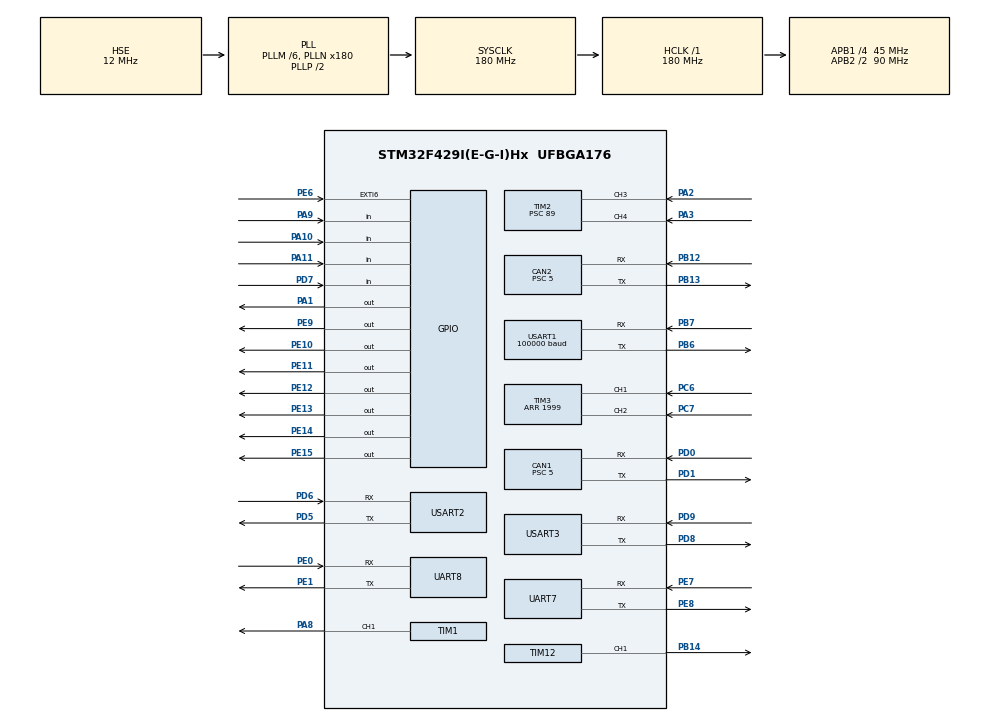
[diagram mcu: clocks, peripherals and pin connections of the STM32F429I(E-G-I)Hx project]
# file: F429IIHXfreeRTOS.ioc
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CAN1.BS1=CAN_BS1_7TQ
CAN1.CalculateTimeQuantum=111.11111111111111
CAN1.Prescaler=5
CAN1.SJW=CAN_SJW_2TQ
CAN2.BS1=CAN_BS1_7TQ
CAN2.CalculateTimeQuantum=111.11111111111111
CAN2.Prescaler=5
CAN2.SJW=CAN_SJW_2TQ
Dma.Request0=UART7_RX
Dma.Request1=USART1_RX
Dma.Request2=USART2_RX
Dma.Request3=USART3_RX
Dma.Request4=UART8_RX
Dma.UART7_RX.0.Direction=DMA_PERIPH_TO_MEMORY
Dma.UART7_RX.0.FIFOMode=DMA_FIFOMODE_DISABLE
Dma.UART7_RX.0.Instance=DMA1_Stream3
Dma.UART7_RX.0.MemDataAlignment=DMA_MDATAALIGN_BYTE
Dma.UART7_RX.0.MemInc=DMA_MINC_ENABLE
Dma.UART7_RX.0.Mode=DMA_NORMAL
Dma.UART7_RX.0.PeriphDataAlignment=DMA_PDATAALIGN_BYTE
Dma.UART7_RX.0.PeriphInc=DMA_PINC_DISABLE
Dma.UART7_RX.0.Priority=DMA_PRIORITY_LOW
Dma.UART8_RX.4.Direction=DMA_PERIPH_TO_MEMORY
Dma.UART8_RX.4.FIFOMode=DMA_FIFOMODE_DISABLE
Dma.UART8_RX.4.Instance=DMA1_Stream6
Dma.UART8_RX.4.MemDataAlignment=DMA_MDATAALIGN_BYTE
Dma.UART8_RX.4.MemInc=DMA_MINC_ENABLE
Dma.UART8_RX.4.Mode=DMA_NORMAL
Dma.UART8_RX.4.PeriphDataAlignment=DMA_PDATAALIGN_BYTE
Dma.UART8_RX.4.PeriphInc=DMA_PINC_DISABLE
Dma.UART8_RX.4.Priority=DMA_PRIORITY_LOW
Dma.USART1_RX.1.Direction=DMA_PERIPH_TO_MEMORY
Dma.USART1_RX.1.FIFOMode=DMA_FIFOMODE_DISABLE
Dma.USART1_RX.1.Instance=DMA2_Stream2
Dma.USART1_RX.1.MemDataAlignment=DMA_MDATAALIGN_BYTE
Dma.USART1_RX.1.MemInc=DMA_MINC_ENABLE
Dma.USART1_RX.1.Mode=DMA_NORMAL
Dma.USART1_RX.1.PeriphDataAlignment=DMA_PDATAALIGN_BYTE
Dma.USART1_RX.1.PeriphInc=DMA_PINC_DISABLE
Dma.USART1_RX.1.Priority=DMA_PRIORITY_LOW
Dma.USART2_RX.2.Direction=DMA_PERIPH_TO_MEMORY
Dma.USART2_RX.2.FIFOMode=DMA_FIFOMODE_DISABLE
Dma.USART2_RX.2.Instance=DMA1_Stream5
Dma.USART2_RX.2.MemDataAlignment=DMA_MDATAALIGN_BYTE
Dma.USART2_RX.2.MemInc=DMA_MINC_ENABLE
Dma.USART2_RX.2.Mode=DMA_NORMAL
Dma.USART2_RX.2.PeriphDataAlignment=DMA_PDATAALIGN_BYTE
Dma.USART2_RX.2.PeriphInc=DMA_PINC_DISABLE
Dma.USART2_RX.2.Priority=DMA_PRIORITY_LOW
Dma.USART3_RX.3.Direction=DMA_PERIPH_TO_MEMORY
Dma.USART3_RX.3.FIFOMode=DMA_FIFOMODE_DISABLE
Dma.USART3_RX.3.Instance=DMA1_Stream1
Dma.USART3_RX.3.MemDataAlignment=DMA_MDATAALIGN_BYTE
Dma.USART3_RX.3.MemInc=DMA_MINC_ENABLE
Dma.USART3_RX.3.Mode=DMA_NORMAL
Dma.USART3_RX.3.PeriphDataAlignment=DMA_PDATAALIGN_BYTE
Dma.USART3_RX.3.PeriphInc=DMA_PINC_DISABLE
Dma.USART3_RX.3.Priority=DMA_PRIORITY_LOW
FREERTOS.Tasks01=defaultTask,0,128,StartDefaultTask,Default,NULL
FREERTOS.configGENERATE_RUN_TIME_STATS=1
FREERTOS.configUSE_STATS_FORMATTING_FUNCTIONS=1
FREERTOS.configUSE_TRACE_FACILITY=1
Mcu.Family=STM32F4
Mcu.Name=STM32F429I(E-G-I)Hx
Mcu.Package=UFBGA176
NVIC.CAN1_RX0_IRQn=true\:6\:0\:true\:false\:true\:true\:true\:true
NVIC.CAN2_RX0_IRQn=true\:5\:0\:false\:false\:true\:true\:true\:true
NVIC.DMA1_Stream1_IRQn=true\:5\:0\:false\:false\:true\:true\:false\:true
NVIC.DMA1_Stream3_IRQn=true\:5\:0\:false\:false\:true\:true\:false\:true
NVIC.DMA1_Stream5_IRQn=true\:5\:0\:false\:false\:true\:true\:false\:true
NVIC.DMA1_Stream6_IRQn=true\:5\:0\:false\:false\:true\:true\:false\:true
NVIC.DMA2_Stream2_IRQn=true\:5\:0\:false\:false\:true\:true\:false\:true
NVIC.EXTI9_5_IRQn=true\:5\:0\:false\:false\:true\:true\:true\:true
NVIC.PriorityGroup=NVIC_PRIORITYGROUP_4
NVIC.TIM2_IRQn=true\:5\:0\:false\:false\:true\:true\:true\:true
NVIC.TIM6_DAC_IRQn=true\:0\:0\:false\:false\:true\:false\:false\:true
NVIC.TIM7_IRQn=true\:5\:0\:false\:false\:true\:true\:true\:true
NVIC.TimeBase=TIM6_DAC_IRQn
NVIC.TimeBaseIP=TIM6
NVIC.UART7_IRQn=true\:6\:0\:true\:false\:true\:true\:true\:true
NVIC.UART8_IRQn=true\:5\:0\:false\:false\:true\:true\:true\:true
NVIC.USART1_IRQn=true\:5\:0\:false\:false\:true\:true\:true\:true
NVIC.USART2_IRQn=true\:6\:0\:true\:false\:true\:true\:true\:true
NVIC.USART3_IRQn=true\:7\:0\:true\:false\:true\:true\:true\:true
PA1.Signal=GPIO_Output
PA10.Signal=GPIO_Input
PA11.Signal=GPIO_Input
PA13.Mode=Serial_Wire
PA13.Signal=SYS_JTMS-SWDIO
PA14.Mode=Serial_Wire
PA14.Signal=SYS_JTCK-SWCLK
PA2.Signal=S_TIM2_CH3
PA3.Signal=S_TIM2_CH4
PA8.Signal=S_TIM1_CH1
PA9.Signal=GPIO_Input
PB12.Mode=Slave
PB12.Signal=CAN2_RX
PB13.Mode=Slave
PB13.Signal=CAN2_TX
PB14.Signal=S_TIM12_CH1
PB6.Mode=Asynchronous
PB6.Signal=USART1_TX
PB7.Mode=Asynchronous
PB7.Signal=USART1_RX
PC6.GPIO_PuPd=GPIO_PULLUP
PC6.Signal=S_TIM3_CH1
PC7.GPIO_PuPd=GPIO_PULLUP
PC7.Signal=S_TIM3_CH2
PD0.Mode=Master
PD0.Signal=CAN1_RX
PD1.Mode=Master
PD1.Signal=CAN1_TX
PD5.Mode=Asynchronous
PD5.Signal=USART2_TX
PD6.Mode=Asynchronous
PD6.Signal=USART2_RX
PD7.Signal=GPIO_Input
PD8.Mode=Asynchronous
PD8.Signal=USART3_TX
PD9.Mode=Asynchronous
PD9.Signal=USART3_RX
PE0.Mode=Asynchronous
PE0.Signal=UART8_RX
PE1.Mode=Asynchronous
PE1.Signal=UART8_TX
PE10.Signal=GPIO_Output
PE11.Signal=GPIO_Output
PE12.Signal=GPIO_Output
PE13.Signal=GPIO_Output
PE14.Signal=GPIO_Output
PE15.Signal=GPIO_Output
PE6.GPIO_PuPd=GPIO_PULLUP
PE6.Signal=GPXTI6
PE7.Mode=Asynchronous
PE7.Signal=UART7_RX
PE8.Mode=Asynchronous
PE8.Signal=UART7_TX
PE9.Signal=GPIO_Output
PH0/OSC_IN.Mode=HSE-External-Oscillator
PH0/OSC_IN.Signal=RCC_OSC_IN
PH1/OSC_OUT.Mode=HSE-External-Oscillator
PH1/OSC_OUT.Signal=RCC_OSC_OUT
ProjectManager.HeapSize=0x1000
ProjectManager.StackSize=0x800
ProjectManager.TargetToolchain=MDK-ARM V5
RCC.48MHZClocksFreq_Value=90000000
RCC.AHBFreq_Value=180000000
RCC.APB1CLKDivider=RCC_HCLK_DIV4
RCC.APB1Freq_Value=45000000
RCC.APB1TimFreq_Value=90000000
RCC.APB2CLKDivider=RCC_HCLK_DIV2
RCC.APB2Freq_Value=90000000
RCC.APB2TimFreq_Value=180000000
RCC.CortexFreq_Value=180000000
RCC.HCLKFreq_Value=180000000
RCC.HSE_VALUE=12000000
RCC.HSI_VALUE=16000000
RCC.LSE_VALUE=32768
RCC.PLLM=6
RCC.PLLN=180
RCC.PLLSourceVirtual=RCC_PLLSOURCE_HSE
RCC.SYSCLKFreq_VALUE=180000000
RCC.SYSCLKSource=RCC_SYSCLKSOURCE_PLLCLK
RCC.VCOOutputFreq_Value=360000000
SH.S_TIM12_CH1.0=TIM12_CH1,PWM Generation1 CH1
SH.S_TIM1_CH1.0=TIM1_CH1,PWM Generation1 CH1
SH.S_TIM2_CH3.0=TIM2_CH3,Input_Capture3_from_TI3
SH.S_TIM2_CH4.0=TIM2_CH4,Input_Capture4_from_TI4
SH.S_TIM3_CH1.0=TIM3_CH1,Encoder_Interface
SH.S_TIM3_CH2.0=TIM3_CH2,Encoder_Interface
TIM1.Channel-PWM\ Generation1\ CH1=TIM_CHANNEL_1
TIM1.Period=19999
TIM1.Prescaler=179
TIM12.Channel-PWM\ Generation1\ CH1=TIM_CHANNEL_1
TIM12.Period=19999
TIM12.Prescaler=89
TIM2.Channel-Input_Capture3_from_TI3=TIM_CHANNEL_3
TIM2.Channel-Input_Capture4_from_TI4=TIM_CHANNEL_4
TIM2.ICFilter_CH3=4
TIM2.ICFilter_CH4=4
TIM2.Period=0xFFFF-1
TIM2.Prescaler=89
TIM3.EncoderMode=TIM_ENCODERMODE_TI12
TIM3.Period=1999
TIM7.Period=19999
TIM7.Prescaler=89
UART7.VirtualMode=Asynchronous
UART8.VirtualMode=Asynchronous
USART1.BaudRate=100000
USART1.Parity=PARITY_EVEN
USART1.VirtualMode=VM_ASYNC
USART2.VirtualMode=VM_ASYNC
USART3.VirtualMode=VM_ASYNC
VP_FREERTOS_VS_CMSIS_V1.Mode=CMSIS_V1
VP_SYS_VS_tim6.Mode=TIM6
VP_TIM12_VS_ClockSourceINT.Mode=Internal
VP_TIM2_VS_ClockSourceINT.Mode=Internal
VP_TIM7_VS_ClockSourceINT.Mode=Enable_Timer
board=custom

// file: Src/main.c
/* USER CODE BEGIN Header */
/**
  ******************************************************************************
  * @file           : main.c
  * @brief          : Main program body
  ******************************************************************************
  * @attention
  *
  * <h2><center>&copy; Copyright (c) 2019 STMicroelectronics.
  * All rights reserved.</center></h2>
  *
  * This software component is licensed by ST under Ultimate Liberty license
  * SLA0044, the "License"; You may not use this file except in compliance with
  * the License. You may obtain a copy of the License at:
  *                             www.st.com/SLA0044
  *
  ******************************************************************************
  */
/* USER CODE END Header */

#include "main.h"
#include "cmsis_os.h"

/* USER CODE BEGIN Includes */
#include "user.h"
/* USER CODE END Includes */

CAN_HandleTypeDef hcan1;
CAN_HandleTypeDef hcan2;

TIM_HandleTypeDef htim1;
TIM_HandleTypeDef htim2;
TIM_HandleTypeDef htim3;
TIM_HandleTypeDef htim7;
TIM_HandleTypeDef htim12;

UART_HandleTypeDef huart7;
UART_HandleTypeDef huart8;
UART_HandleTypeDef huart1;
UART_HandleTypeDef huart2;
UART_HandleTypeDef huart3;
DMA_HandleTypeDef hdma_uart7_rx;
DMA_HandleTypeDef hdma_uart8_rx;
DMA_HandleTypeDef hdma_usart1_rx;
DMA_HandleTypeDef hdma_usart2_rx;
DMA_HandleTypeDef hdma_usart3_rx;

osThreadId defaultTaskHandle;

void SystemClock_Config(void);
static void MX_GPIO_Init(void);
static void MX_DMA_Init(void);
static void MX_CAN1_Init(void);
static void MX_GFXSIMULATOR_Init(void);
static void MX_TIM1_Init(void);
static void MX_TIM3_Init(void);
static void MX_TIM7_Init(void);
static void MX_TIM12_Init(void);
static void MX_UART7_Init(void);
static void MX_USART1_UART_Init(void);
static void MX_USART2_UART_Init(void);
static void MX_USART3_UART_Init(void);
static void MX_CAN2_Init(void);
static void MX_UART8_Init(void);
static void MX_TIM2_Init(void);
void StartDefaultTask(void const * argument);

int main(void)
  {

  /* MCU Configuration--------------------------------------------------------*/

  /* Reset of all peripherals, Initializes the Flash interface and the Systick. */
  HAL_Init();

  /* Configure the system clock */
  SystemClock_Config();

  /* Initialize all configured peripherals */
  MX_GPIO_Init();
  MX_DMA_Init();
  MX_CAN1_Init();
  MX_GFXSIMULATOR_Init();
  MX_TIM1_Init();
  MX_TIM3_Init();
  MX_TIM7_Init();
  MX_TIM12_Init();
  MX_UART7_Init();
  MX_USART1_UART_Init();
  MX_USART2_UART_Init();
  MX_USART3_UART_Init();
  MX_CAN2_Init();
  MX_UART8_Init();
  MX_TIM2_Init();

  /* Create the thread(s) */
  /* definition and creation of defaultTask */
  osThreadDef(defaultTask, StartDefaultTask, osPriorityNormal, 0, 128);
  defaultTaskHandle = osThreadCreate(osThread(defaultTask), NULL);

  /* USER CODE BEGIN RTOS_THREADS */
  /* add threads, ... */
    SysInit();
  /* USER CODE END RTOS_THREADS */

  /* Start scheduler */
  osKernelStart();

  /* We should never get here as control is now taken by the scheduler */

  /* Infinite loop */
  while (1)
  {

  }
}

void SystemClock_Config(void)
{
  RCC_OscInitTypeDef RCC_OscInitStruct = {0};
  RCC_ClkInitTypeDef RCC_ClkInitStruct = {0};

  /** Configure the main internal regulator output voltage
  */
  __HAL_RCC_PWR_CLK_ENABLE();
  __HAL_PWR_VOLTAGESCALING_CONFIG(PWR_REGULATOR_VOLTAGE_SCALE1);
  /** Initializes the CPU, AHB and APB busses clocks
  */
  RCC_OscInitStruct.OscillatorType = RCC_OSCILLATORTYPE_HSE;
  RCC_OscInitStruct.HSEState = RCC_HSE_ON;
  RCC_OscInitStruct.PLL.PLLState = RCC_PLL_ON;
  RCC_OscInitStruct.PLL.PLLSource = RCC_PLLSOURCE_HSE;
  RCC_OscInitStruct.PLL.PLLM = 6;
  RCC_OscInitStruct.PLL.PLLN = 180;
  RCC_OscInitStruct.PLL.PLLP = RCC_PLLP_DIV2;
  RCC_OscInitStruct.PLL.PLLQ = 4;
  if (HAL_RCC_OscConfig(&RCC_OscInitStruct) != HAL_OK)
  {
    Error_Handler();
  }
  /** Activate the Over-Drive mode
  */
  if (HAL_PWREx_EnableOverDrive() != HAL_OK)
  {
    Error_Handler();
  }
  /** Initializes the CPU, AHB and APB busses clocks
  */
  RCC_ClkInitStruct.ClockType = RCC_CLOCKTYPE_HCLK|RCC_CLOCKTYPE_SYSCLK
                              |RCC_CLOCKTYPE_PCLK1|RCC_CLOCKTYPE_PCLK2;
  RCC_ClkInitStruct.SYSCLKSource = RCC_SYSCLKSOURCE_PLLCLK;
  RCC_ClkInitStruct.AHBCLKDivider = RCC_SYSCLK_DIV1;
  RCC_ClkInitStruct.APB1CLKDivider = RCC_HCLK_DIV4;
  RCC_ClkInitStruct.APB2CLKDivider = RCC_HCLK_DIV2;

  if (HAL_RCC_ClockConfig(&RCC_ClkInitStruct, FLASH_LATENCY_5) != HAL_OK)
  {
    Error_Handler();
  }
}

static void MX_CAN1_Init(void)
{

  hcan1.Instance = CAN1;
  hcan1.Init.Prescaler = 5;
  hcan1.Init.Mode = CAN_MODE_NORMAL;
  hcan1.Init.SyncJumpWidth = CAN_SJW_2TQ;
  hcan1.Init.TimeSeg1 = CAN_BS1_7TQ;
  hcan1.Init.TimeSeg2 = CAN_BS2_1TQ;
  hcan1.Init.TimeTriggeredMode = DISABLE;
  hcan1.Init.AutoBusOff = DISABLE;
  hcan1.Init.AutoWakeUp = DISABLE;
  hcan1.Init.AutoRetransmission = DISABLE;
  hcan1.Init.ReceiveFifoLocked = DISABLE;
  hcan1.Init.TransmitFifoPriority = DISABLE;
  if (HAL_CAN_Init(&hcan1) != HAL_OK)
  {
    Error_Handler();
  }

}

static void MX_CAN2_Init(void)
{

  hcan2.Instance = CAN2;
  hcan2.Init.Prescaler = 5;
  hcan2.Init.Mode = CAN_MODE_NORMAL;
  hcan2.Init.SyncJumpWidth = CAN_SJW_2TQ;
  hcan2.Init.TimeSeg1 = CAN_BS1_7TQ;
  hcan2.Init.TimeSeg2 = CAN_BS2_1TQ;
  hcan2.Init.TimeTriggeredMode = DISABLE;
  hcan2.Init.AutoBusOff = DISABLE;
  hcan2.Init.AutoWakeUp = DISABLE;
  hcan2.Init.AutoRetransmission = DISABLE;
  hcan2.Init.ReceiveFifoLocked = DISABLE;
  hcan2.Init.TransmitFifoPriority = DISABLE;
  if (HAL_CAN_Init(&hcan2) != HAL_OK)
  {
    Error_Handler();
  }

}

static void MX_GFXSIMULATOR_Init(void)
{

}

static void MX_TIM1_Init(void)
{

  TIM_MasterConfigTypeDef sMasterConfig = {0};
  TIM_OC_InitTypeDef sConfigOC = {0};
  TIM_BreakDeadTimeConfigTypeDef sBreakDeadTimeConfig = {0};

  htim1.Instance = TIM1;
  htim1.Init.Prescaler = 179;
  htim1.Init.CounterMode = TIM_COUNTERMODE_UP;
  htim1.Init.Period = 19999;
  htim1.Init.ClockDivision = TIM_CLOCKDIVISION_DIV1;
  htim1.Init.RepetitionCounter = 0;
  htim1.Init.AutoReloadPreload = TIM_AUTORELOAD_PRELOAD_DISABLE;
  if (HAL_TIM_PWM_Init(&htim1) != HAL_OK)
  {
    Error_Handler();
  }
  sMasterConfig.MasterOutputTrigger = TIM_TRGO_RESET;
  sMasterConfig.MasterSlaveMode = TIM_MASTERSLAVEMODE_DISABLE;
  if (HAL_TIMEx_MasterConfigSynchronization(&htim1, &sMasterConfig) != HAL_OK)
  {
    Error_Handler();
  }
  sConfigOC.OCMode = TIM_OCMODE_PWM1;
  sConfigOC.Pulse = 0;
  sConfigOC.OCPolarity = TIM_OCPOLARITY_HIGH;
  sConfigOC.OCNPolarity = TIM_OCNPOLARITY_HIGH;
  sConfigOC.OCFastMode = TIM_OCFAST_DISABLE;
  sConfigOC.OCIdleState = TIM_OCIDLESTATE_RESET;
  sConfigOC.OCNIdleState = TIM_OCNIDLESTATE_RESET;
  if (HAL_TIM_PWM_ConfigChannel(&htim1, &sConfigOC, TIM_CHANNEL_1) != HAL_OK)
  {
    Error_Handler();
  }
  sBreakDeadTimeConfig.OffStateRunMode = TIM_OSSR_DISABLE;
  sBreakDeadTimeConfig.OffStateIDLEMode = TIM_OSSI_DISABLE;
  sBreakDeadTimeConfig.LockLevel = TIM_LOCKLEVEL_OFF;
  sBreakDeadTimeConfig.DeadTime = 0;
  sBreakDeadTimeConfig.BreakState = TIM_BREAK_DISABLE;
  sBreakDeadTimeConfig.BreakPolarity = TIM_BREAKPOLARITY_HIGH;
  sBreakDeadTimeConfig.AutomaticOutput = TIM_AUTOMATICOUTPUT_DISABLE;
  if (HAL_TIMEx_ConfigBreakDeadTime(&htim1, &sBreakDeadTimeConfig) != HAL_OK)
  {
    Error_Handler();
  }
  HAL_TIM_MspPostInit(&htim1);

}

static void MX_TIM2_Init(void)
{

  TIM_ClockConfigTypeDef sClockSourceConfig = {0};
  TIM_MasterConfigTypeDef sMasterConfig = {0};
  TIM_IC_InitTypeDef sConfigIC = {0};

  htim2.Instance = TIM2;
  htim2.Init.Prescaler = 89;
  htim2.Init.CounterMode = TIM_COUNTERMODE_UP;
  htim2.Init.Period = 0xFFFF-1;
  htim2.Init.ClockDivision = TIM_CLOCKDIVISION_DIV1;
  htim2.Init.AutoReloadPreload = TIM_AUTORELOAD_PRELOAD_DISABLE;
  if (HAL_TIM_Base_Init(&htim2) != HAL_OK)
  {
    Error_Handler();
  }
  sClockSourceConfig.ClockSource = TIM_CLOCKSOURCE_INTERNAL;
  if (HAL_TIM_ConfigClockSource(&htim2, &sClockSourceConfig) != HAL_OK)
  {
    Error_Handler();
  }
  if (HAL_TIM_IC_Init(&htim2) != HAL_OK)
  {
    Error_Handler();
  }
  sMasterConfig.MasterOutputTrigger = TIM_TRGO_RESET;
  sMasterConfig.MasterSlaveMode = TIM_MASTERSLAVEMODE_DISABLE;
  if (HAL_TIMEx_MasterConfigSynchronization(&htim2, &sMasterConfig) != HAL_OK)
  {
    Error_Handler();
  }
  sConfigIC.ICPolarity = TIM_INPUTCHANNELPOLARITY_RISING;
  sConfigIC.ICSelection = TIM_ICSELECTION_DIRECTTI;
  sConfigIC.ICPrescaler = TIM_ICPSC_DIV1;
  sConfigIC.ICFilter = 4;
  if (HAL_TIM_IC_ConfigChannel(&htim2, &sConfigIC, TIM_CHANNEL_3) != HAL_OK)
  {
    Error_Handler();
  }
  if (HAL_TIM_IC_ConfigChannel(&htim2, &sConfigIC, TIM_CHANNEL_4) != HAL_OK)
  {
    Error_Handler();
  }

}

static void MX_TIM3_Init(void)
{

  TIM_Encoder_InitTypeDef sConfig = {0};
  TIM_MasterConfigTypeDef sMasterConfig = {0};

  htim3.Instance = TIM3;
  htim3.Init.Prescaler = 0;
  htim3.Init.CounterMode = TIM_COUNTERMODE_UP;
  htim3.Init.Period = 1999;
  htim3.Init.ClockDivision = TIM_CLOCKDIVISION_DIV1;
  htim3.Init.AutoReloadPreload = TIM_AUTORELOAD_PRELOAD_DISABLE;
  sConfig.EncoderMode = TIM_ENCODERMODE_TI12;
  sConfig.IC1Polarity = TIM_ICPOLARITY_RISING;
  sConfig.IC1Selection = TIM_ICSELECTION_DIRECTTI;
  sConfig.IC1Prescaler = TIM_ICPSC_DIV1;
  sConfig.IC1Filter = 0;
  sConfig.IC2Polarity = TIM_ICPOLARITY_RISING;
  sConfig.IC2Selection = TIM_ICSELECTION_DIRECTTI;
  sConfig.IC2Prescaler = TIM_ICPSC_DIV1;
  sConfig.IC2Filter = 0;
  if (HAL_TIM_Encoder_Init(&htim3, &sConfig) != HAL_OK)
  {
    Error_Handler();
  }
  sMasterConfig.MasterOutputTrigger = TIM_TRGO_RESET;
  sMasterConfig.MasterSlaveMode = TIM_MASTERSLAVEMODE_DISABLE;
  if (HAL_TIMEx_MasterConfigSynchronization(&htim3, &sMasterConfig) != HAL_OK)
  {
    Error_Handler();
  }

}

static void MX_TIM7_Init(void)
{

  TIM_MasterConfigTypeDef sMasterConfig = {0};

  htim7.Instance = TIM7;
  htim7.Init.Prescaler = 89;
  htim7.Init.CounterMode = TIM_COUNTERMODE_UP;
  htim7.Init.Period = 19999;
  htim7.Init.AutoReloadPreload = TIM_AUTORELOAD_PRELOAD_DISABLE;
  if (HAL_TIM_Base_Init(&htim7) != HAL_OK)
  {
    Error_Handler();
  }
  sMasterConfig.MasterOutputTrigger = TIM_TRGO_RESET;
  sMasterConfig.MasterSlaveMode = TIM_MASTERSLAVEMODE_DISABLE;
  if (HAL_TIMEx_MasterConfigSynchronization(&htim7, &sMasterConfig) != HAL_OK)
  {
    Error_Handler();
  }

}

static void MX_TIM12_Init(void)
{

  TIM_ClockConfigTypeDef sClockSourceConfig = {0};
  TIM_OC_InitTypeDef sConfigOC = {0};

  htim12.Instance = TIM12;
  htim12.Init.Prescaler = 89;
  htim12.Init.CounterMode = TIM_COUNTERMODE_UP;
  htim12.Init.Period = 19999;
  htim12.Init.ClockDivision = TIM_CLOCKDIVISION_DIV1;
  htim12.Init.AutoReloadPreload = TIM_AUTORELOAD_PRELOAD_DISABLE;
  if (HAL_TIM_Base_Init(&htim12) != HAL_OK)
  {
    Error_Handler();
  }
  sClockSourceConfig.ClockSource = TIM_CLOCKSOURCE_INTERNAL;
  if (HAL_TIM_ConfigClockSource(&htim12, &sClockSourceConfig) != HAL_OK)
  {
    Error_Handler();
  }
  if (HAL_TIM_PWM_Init(&htim12) != HAL_OK)
  {
    Error_Handler();
  }
  sConfigOC.OCMode = TIM_OCMODE_PWM1;
  sConfigOC.Pulse = 0;
  sConfigOC.OCPolarity = TIM_OCPOLARITY_HIGH;
  sConfigOC.OCFastMode = TIM_OCFAST_DISABLE;
  if (HAL_TIM_PWM_ConfigChannel(&htim12, &sConfigOC, TIM_CHANNEL_1) != HAL_OK)
  {
    Error_Handler();
  }
  HAL_TIM_MspPostInit(&htim12);

}

static void MX_UART7_Init(void)
{

  huart7.Instance = UART7;
  huart7.Init.BaudRate = 115200;
  huart7.Init.WordLength = UART_WORDLENGTH_8B;
  huart7.Init.StopBits = UART_STOPBITS_1;
  huart7.Init.Parity = UART_PARITY_NONE;
  huart7.Init.Mode = UART_MODE_TX_RX;
  huart7.Init.HwFlowCtl = UART_HWCONTROL_NONE;
  huart7.Init.OverSampling = UART_OVERSAMPLING_16;
  if (HAL_UART_Init(&huart7) != HAL_OK)
  {
    Error_Handler();
  }

}

static void MX_UART8_Init(void)
{

  huart8.Instance = UART8;
  huart8.Init.BaudRate = 115200;
  huart8.Init.WordLength = UART_WORDLENGTH_8B;
  huart8.Init.StopBits = UART_STOPBITS_1;
  huart8.Init.Parity = UART_PARITY_NONE;
  huart8.Init.Mode = UART_MODE_TX_RX;
  huart8.Init.HwFlowCtl = UART_HWCONTROL_NONE;
  huart8.Init.OverSampling = UART_OVERSAMPLING_16;
  if (HAL_UART_Init(&huart8) != HAL_OK)
  {
    Error_Handler();
  }

}

static void MX_USART1_UART_Init(void)
{

  huart1.Instance = USART1;
  huart1.Init.BaudRate = 100000;
  huart1.Init.WordLength = UART_WORDLENGTH_8B;
  huart1.Init.StopBits = UART_STOPBITS_1;
  huart1.Init.Parity = UART_PARITY_EVEN;
  huart1.Init.Mode = UART_MODE_TX_RX;
  huart1.Init.HwFlowCtl = UART_HWCONTROL_NONE;
  huart1.Init.OverSampling = UART_OVERSAMPLING_16;
  if (HAL_UART_Init(&huart1) != HAL_OK)
  {
    Error_Handler();
  }

}

static void MX_USART2_UART_Init(void)
{

  huart2.Instance = USART2;
  huart2.Init.BaudRate = 1000000;
  huart2.Init.WordLength = UART_WORDLENGTH_8B;
  huart2.Init.StopBits = UART_STOPBITS_1;
  huart2.Init.Parity = UART_PARITY_NONE;
  huart2.Init.Mode = UART_MODE_TX_RX;
  huart2.Init.HwFlowCtl = UART_HWCONTROL_NONE;
  huart2.Init.OverSampling = UART_OVERSAMPLING_16;
  if (HAL_UART_Init(&huart2) != HAL_OK)
  {
    Error_Handler();
  }

}

static void MX_USART3_UART_Init(void)
{

  huart3.Instance = USART3;
  huart3.Init.BaudRate = 115200;
  huart3.Init.WordLength = UART_WORDLENGTH_8B;
  huart3.Init.StopBits = UART_STOPBITS_1;
  huart3.Init.Parity = UART_PARITY_NONE;
  huart3.Init.Mode = UART_MODE_TX_RX;
  huart3.Init.HwFlowCtl = UART_HWCONTROL_NONE;
  huart3.Init.OverSampling = UART_OVERSAMPLING_16;
  if (HAL_UART_Init(&huart3) != HAL_OK)
  {
    Error_Handler();
  }

}

static void MX_DMA_Init(void)
{
  /* DMA controller clock enable */
  __HAL_RCC_DMA1_CLK_ENABLE();
  __HAL_RCC_DMA2_CLK_ENABLE();

  /* DMA interrupt init */
  /* DMA1_Stream1_IRQn interrupt configuration */
  HAL_NVIC_SetPriority(DMA1_Stream1_IRQn, 5, 0);
  HAL_NVIC_EnableIRQ(DMA1_Stream1_IRQn);
  /* DMA1_Stream3_IRQn interrupt configuration */
  HAL_NVIC_SetPriority(DMA1_Stream3_IRQn, 5, 0);
  HAL_NVIC_EnableIRQ(DMA1_Stream3_IRQn);
  /* DMA1_Stream5_IRQn interrupt configuration */
  HAL_NVIC_SetPriority(DMA1_Stream5_IRQn, 5, 0);
  HAL_NVIC_EnableIRQ(DMA1_Stream5_IRQn);
  /* DMA1_Stream6_IRQn interrupt configuration */
  HAL_NVIC_SetPriority(DMA1_Stream6_IRQn, 5, 0);
  HAL_NVIC_EnableIRQ(DMA1_Stream6_IRQn);
  /* DMA2_Stream2_IRQn interrupt configuration */
  HAL_NVIC_SetPriority(DMA2_Stream2_IRQn, 5, 0);
  HAL_NVIC_EnableIRQ(DMA2_Stream2_IRQn);

}

static void MX_GPIO_Init(void)
{
  GPIO_InitTypeDef GPIO_InitStruct = {0};

  /* GPIO Ports Clock Enable */
  __HAL_RCC_GPIOE_CLK_ENABLE();
  __HAL_RCC_GPIOD_CLK_ENABLE();
  __HAL_RCC_GPIOA_CLK_ENABLE();
  __HAL_RCC_GPIOB_CLK_ENABLE();
  __HAL_RCC_GPIOH_CLK_ENABLE();
  __HAL_RCC_GPIOC_CLK_ENABLE();

  /*Configure GPIO pin Output Level */
  HAL_GPIO_WritePin(GPIOA, GPIO_PIN_1|GPIO_PIN_12, GPIO_PIN_RESET);

  /*Configure GPIO pin Output Level */
  HAL_GPIO_WritePin(GPIOE, GPIO_PIN_13|GPIO_PIN_9|GPIO_PIN_11|GPIO_PIN_14
                          |GPIO_PIN_10|GPIO_PIN_12|GPIO_PIN_15, GPIO_PIN_SET);
  HAL_GPIO_WritePin(GPIOB, GPIO_PIN_4|GPIO_PIN_5, GPIO_PIN_SET);

  /*Configure GPIO pin : PD7 */
  GPIO_InitStruct.Pin = GPIO_PIN_7;
  GPIO_InitStruct.Mode = GPIO_MODE_INPUT;
  GPIO_InitStruct.Pull = GPIO_NOPULL;
  HAL_GPIO_Init(GPIOD, &GPIO_InitStruct);

  /*Configure GPIO pin : PE6 */
  GPIO_InitStruct.Pin = GPIO_PIN_6;
  GPIO_InitStruct.Mode = GPIO_MODE_IT_RISING;
  GPIO_InitStruct.Pull = GPIO_PULLUP;
  HAL_GPIO_Init(GPIOE, &GPIO_InitStruct);

  /*Configure GPIO pins : PA11 PA10 PA9 */
  GPIO_InitStruct.Pin = GPIO_PIN_11|GPIO_PIN_10|GPIO_PIN_9;
  GPIO_InitStruct.Mode = GPIO_MODE_INPUT;
  GPIO_InitStruct.Pull = GPIO_NOPULL;
  HAL_GPIO_Init(GPIOA, &GPIO_InitStruct);

  /*Configure GPIO pin : PA1 */
  GPIO_InitStruct.Pin = GPIO_PIN_1|GPIO_PIN_12;
  GPIO_InitStruct.Mode = GPIO_MODE_OUTPUT_PP;
  GPIO_InitStruct.Pull = GPIO_PULLUP;
  GPIO_InitStruct.Speed = GPIO_SPEED_FREQ_LOW;
  HAL_GPIO_Init(GPIOA, &GPIO_InitStruct);

  /*Configure GPIO pins : PE13 PE9 PE11 PE14
                           PE10 PE12 PE15 */
  GPIO_InitStruct.Pin = GPIO_PIN_13|GPIO_PIN_9|GPIO_PIN_11|GPIO_PIN_14
                          |GPIO_PIN_10|GPIO_PIN_12|GPIO_PIN_15;
  GPIO_InitStruct.Mode = GPIO_MODE_OUTPUT_PP;
  GPIO_InitStruct.Pull = GPIO_NOPULL;
  GPIO_InitStruct.Speed = GPIO_SPEED_FREQ_LOW;
  HAL_GPIO_Init(GPIOE, &GPIO_InitStruct);

  GPIO_InitStruct.Pin = GPIO_PIN_4|GPIO_PIN_5;
  GPIO_InitStruct.Mode = GPIO_MODE_OUTPUT_PP;
  GPIO_InitStruct.Pull = GPIO_NOPULL;
  GPIO_InitStruct.Speed = GPIO_SPEED_FREQ_LOW;
  HAL_GPIO_Init(GPIOB, &GPIO_InitStruct);

  /* EXTI interrupt init*/
  HAL_NVIC_SetPriority(EXTI9_5_IRQn, 5, 0);
  HAL_NVIC_EnableIRQ(EXTI9_5_IRQn);

}

void StartDefaultTask(void const * argument)
{

  /* USER CODE BEGIN 5 */
  /* Infinite loop */
  for(;;)
  {
    osDelay(100);
   // vTaskDelete(defaultTaskHandle);
  }
  /* USER CODE END 5 */
}

void HAL_TIM_PeriodElapsedCallback(TIM_HandleTypeDef *htim)
{
  if (htim->Instance == TIM6) {
    HAL_IncTick();
  }
}

void Error_Handler(void)
{
}

/************************ (C) COPYRIGHT STMicroelectronics *****END OF FILE****/
